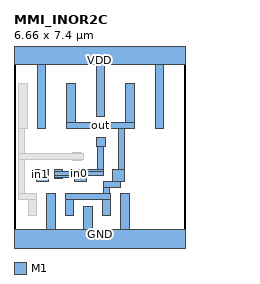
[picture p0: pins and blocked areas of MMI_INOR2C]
MACRO MMI_INOR2C
	CLASS CORE ;
	FOREIGN MMI_INOR2C 0 0 ;
	SIZE 6.66 BY 7.4 ;
	SYMMETRY X Y ;
	SITE CORE1 ;
	PIN out
		DIRECTION output ;
		USE SIGNAL ;
		PORT
			LAYER M1 ;
			RECT 2.05 4.64 2.39 6.17 ;
			LAYER M1 ;
			RECT 4.35 4.64 4.69 6.17 ;
			LAYER M1 ;
			RECT 2.05 4.41 4.69 4.64 ;
			LAYER M1 ;
			RECT 4.06 2.815 4.29 4.41 ;
			LAYER M1 ;
			RECT 3.845 2.365 4.29 2.815 ;
			LAYER M1 ;
			RECT 3.845 2.35 4.14 2.365 ;
			LAYER M1 ;
			RECT 3.49 2.12 4.14 2.35 ;
			LAYER M1 ;
			RECT 3.49 1.88 3.72 2.12 ;
			LAYER M1 ;
			RECT 1.99 1.65 3.77 1.88 ;
			LAYER M1 ;
			RECT 1.99 1.04 2.33 1.65 ;
			LAYER M1 ;
			RECT 3.43 1.04 3.77 1.65 ;
		END
		AntennaDiffArea 2.9808 ;
	END out
	PIN in1
		DIRECTION input ;
		USE SIGNAL ;
		PORT
			LAYER M1 ;
			RECT 0.885 2.81 1.335 2.815 ;
			LAYER M1 ;
			RECT 0.66 2.47 1.335 2.81 ;
			LAYER M1 ;
			RECT 0.885 2.365 1.335 2.47 ;
		END
		AntennaGateArea 0.4968 ;
	END in1
	PIN GND
		DIRECTION inout ;
		USE GROUND ;
		PORT
			LAYER M1 ;
			RECT 1.27 0.5 1.61 1.88 ;
			LAYER M1 ;
			RECT 2.71 0.5 3.05 1.38 ;
			LAYER M1 ;
			RECT 4.15 0.5 4.49 1.88 ;
			LAYER M1 ;
			RECT 0 -0.5 6.66 0.5 ;
		END
	END GND
	PIN VDD
		DIRECTION inout ;
		USE POWER ;
		PORT
			LAYER M1 ;
			RECT 0 6.9 6.66 7.9 ;
			LAYER M1 ;
			RECT 0.9 4.41 1.24 6.9 ;
			LAYER M1 ;
			RECT 3.2 4.89 3.54 6.9 ;
			LAYER M1 ;
			RECT 5.5 4.41 5.84 6.9 ;
		END
	END VDD
	PIN in0
		DIRECTION input ;
		USE SIGNAL ;
		PORT
			LAYER M1 ;
			RECT 3.205 3.725 3.545 4.065 ;
			LAYER M1 ;
			RECT 3.255 2.815 3.485 3.725 ;
			LAYER M1 ;
			RECT 1.565 2.755 1.905 2.81 ;
			LAYER M1 ;
			RECT 2.365 2.755 3.485 2.815 ;
			LAYER M1 ;
			RECT 1.565 2.585 3.485 2.755 ;
			LAYER M1 ;
			RECT 1.565 2.525 2.815 2.585 ;
			LAYER M1 ;
			RECT 1.565 2.47 1.905 2.525 ;
			LAYER M1 ;
			RECT 2.365 2.365 2.815 2.525 ;
		END
		AntennaGateArea 1.656 ;
	END in0
	OBS
		LAYER M1 ;
		RECT 0.18 4.41 0.52 6.17 ;
		LAYER M1 ;
		RECT 0.18 3.445 0.41 4.41 ;
		LAYER M1 ;
		RECT 2.29 3.445 2.63 3.5 ;
		LAYER M1 ;
		RECT 0.18 3.215 2.695 3.445 ;
		LAYER M1 ;
		RECT 0.18 1.88 0.41 3.215 ;
		LAYER M1 ;
		RECT 2.29 3.16 2.63 3.215 ;
		LAYER M1 ;
		RECT 0.18 1.65 0.89 1.88 ;
		LAYER M1 ;
		RECT 0.55 1.04 0.89 1.65 ;
	END
END MMI_INOR2C
